# i3dPDK_A16K CFET_4T cell LEF (1x), from BE/CFET/4T/i3dPDK_A16K_0V7_27C_4T.lef:
# SITE i3d_16A added, coordinates on the 0.5nm grid (signal pins snapped outward, OBS outward).
# i3dPDK_A16K v1.0 (CC BY-NC-SA 4.0, Prof. Taigon Song, I3D VLSI Lab, KNU)
# Read after i3dPDK_A16K_4T_tech.lef.
VERSION 5.8 ;
BUSBITCHARS "[]" ;
DIVIDERCHAR "/" ;


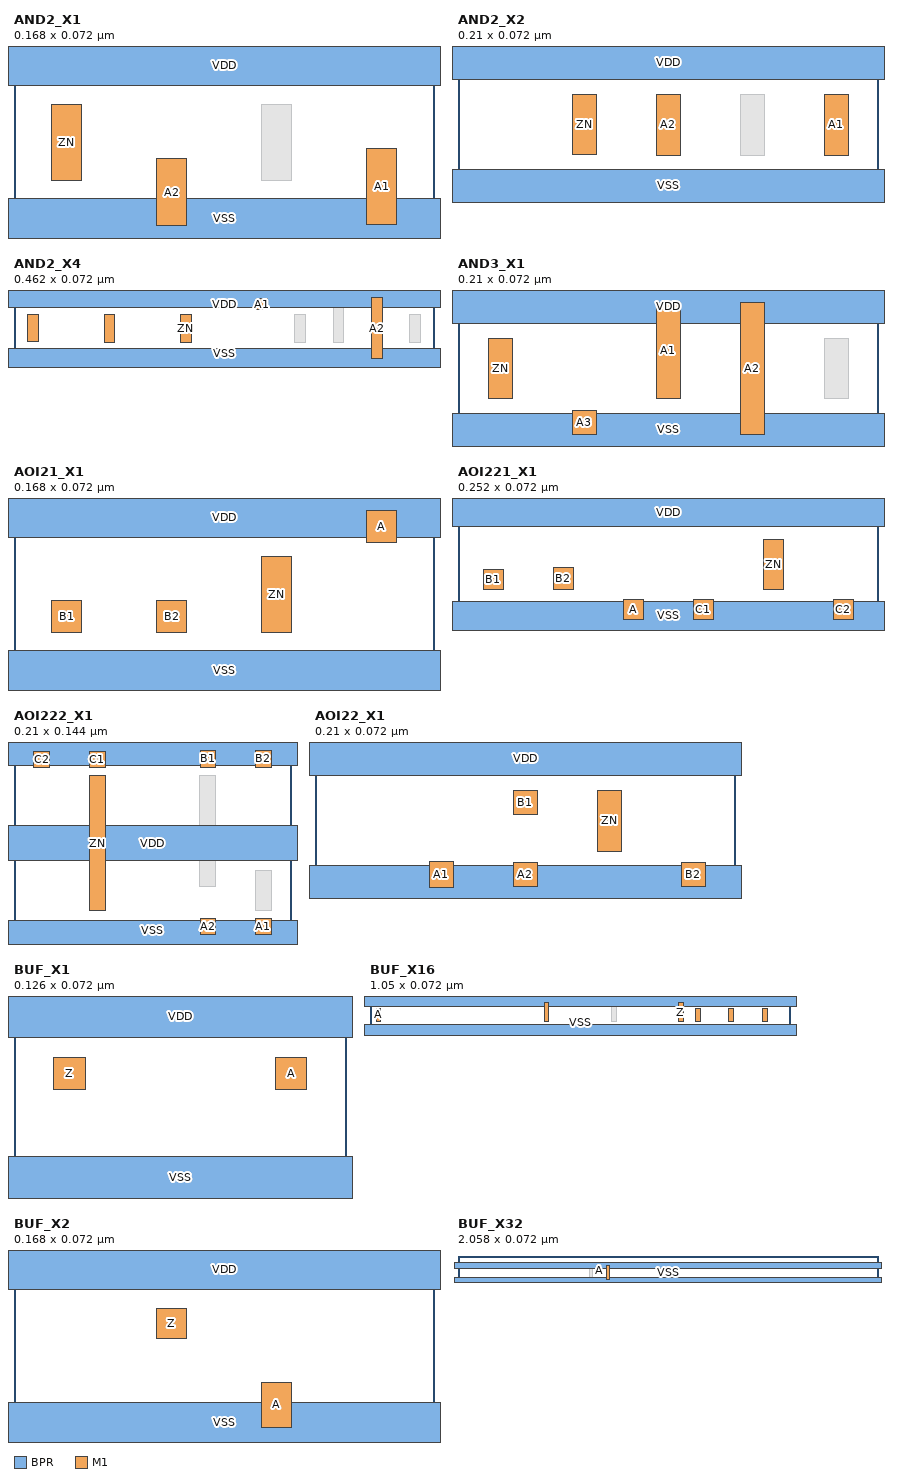
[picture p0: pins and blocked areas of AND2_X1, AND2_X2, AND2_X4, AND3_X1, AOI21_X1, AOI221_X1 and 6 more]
MACRO AND2_X1
  CLASS CORE ;
  FOREIGN AND2_X1 0 0 ;
  ORIGIN 0.0000 0.0000 ;
  SIZE 0.1680 BY 0.0720 ;
  SYMMETRY X Y ;
  SITE i3d_16A ;
  PIN VSS
    DIRECTION INOUT ;
    USE GROUND ;
    PORT
      LAYER BPR ;
        RECT -0.0160 -0.0135 0.1840 0.0135 ;
    END
  END VSS
  PIN VDD
    DIRECTION INOUT ;
    USE POWER ;
    PORT
      LAYER BPR ;
        RECT -0.0160 0.0585 0.1840 0.0855 ;
    END
  END VDD
  PIN A2
    DIRECTION INPUT ;
    USE SIGNAL ;
    PORT
      LAYER M1 ;
        RECT 0.0570 0.0025 0.0690 0.0295 ;
    END
  END A2
  PIN ZN
    DIRECTION OUTPUT ;
    USE SIGNAL ;
    PORT
      LAYER M1 ;
        RECT 0.0150 0.0205 0.0270 0.0510 ;
    END
  END ZN
  PIN A1
    DIRECTION INPUT ;
    USE SIGNAL ;
    PORT
      LAYER M1 ;
        RECT 0.1410 0.0030 0.1530 0.0335 ;
    END
  END A1
  OBS
    LAYER M1 ;
      RECT 0.0990 0.0205 0.1110 0.0510 ;
  END
END AND2_X1

MACRO AND2_X2
  CLASS CORE ;
  FOREIGN AND2_X2 0 0 ;
  ORIGIN 0.0000 0.0000 ;
  SIZE 0.2100 BY 0.0720 ;
  SYMMETRY X Y ;
  SITE i3d_16A ;
  PIN VDD
    DIRECTION INOUT ;
    USE POWER ;
    PORT
      LAYER BPR ;
        RECT -0.0160 0.0585 0.2260 0.0855 ;
    END
  END VDD
  PIN VSS
    DIRECTION INOUT ;
    USE GROUND ;
    PORT
      LAYER BPR ;
        RECT -0.0160 -0.0135 0.2260 0.0135 ;
    END
  END VSS
  PIN A1
    DIRECTION INPUT ;
    USE SIGNAL ;
    PORT
      LAYER M1 ;
        RECT 0.1830 0.0205 0.1950 0.0510 ;
    END
  END A1
  PIN A2
    DIRECTION INPUT ;
    USE SIGNAL ;
    PORT
      LAYER M1 ;
        RECT 0.0990 0.0205 0.1110 0.0510 ;
    END
  END A2
  PIN ZN
    DIRECTION OUTPUT ;
    USE SIGNAL ;
    PORT
      LAYER M1 ;
        RECT 0.0570 0.0210 0.0690 0.0510 ;
    END
  END ZN
  OBS
    LAYER M1 ;
      RECT 0.1410 0.0205 0.1530 0.0510 ;
  END
END AND2_X2

MACRO AND2_X4
  CLASS CORE ;
  FOREIGN AND2_X4 0 0 ;
  ORIGIN 0.0000 0.0000 ;
  SIZE 0.4620 BY 0.0720 ;
  SYMMETRY X Y ;
  SITE i3d_16A ;
  PIN VDD
    DIRECTION INOUT ;
    USE POWER ;
    PORT
      LAYER BPR ;
        RECT -0.0160 0.0585 0.4780 0.0855 ;
    END
  END VDD
  PIN VSS
    DIRECTION INOUT ;
    USE GROUND ;
    PORT
      LAYER BPR ;
        RECT -0.0160 -0.0135 0.4780 0.0135 ;
    END
  END VSS
  PIN ZN
    DIRECTION OUTPUT ;
    USE SIGNAL ;
    PORT
      LAYER M1 ;
        RECT 0.1830 0.0205 0.1950 0.0510 ;
        RECT 0.0990 0.0205 0.1110 0.0510 ;
        RECT 0.0150 0.0210 0.0270 0.0510 ;
    END
  END ZN
  PIN A1
    DIRECTION INPUT ;
    USE SIGNAL ;
    PORT
      LAYER M1 ;
        RECT 0.2670 0.0570 0.2790 0.0690 ;
    END
  END A1
  PIN A2
    DIRECTION INPUT ;
    USE SIGNAL ;
    PORT
      LAYER M1 ;
        RECT 0.3930 0.0025 0.4050 0.0695 ;
    END
  END A2
  OBS
    LAYER M1 ;
      RECT 0.4350 0.0205 0.4470 0.0510 ;
      RECT 0.3090 0.0205 0.3210 0.0510 ;
      RECT 0.3510 0.0205 0.3630 0.0695 ;
  END
END AND2_X4

MACRO AND3_X1
  CLASS CORE ;
  FOREIGN AND3_X1 0 0 ;
  ORIGIN 0.0000 0.0000 ;
  SIZE 0.2100 BY 0.0720 ;
  SYMMETRY X Y ;
  SITE i3d_16A ;
  PIN VSS
    DIRECTION INOUT ;
    USE GROUND ;
    PORT
      LAYER BPR ;
        RECT -0.0160 -0.0135 0.2260 0.0135 ;
    END
  END VSS
  PIN VDD
    DIRECTION INOUT ;
    USE POWER ;
    PORT
      LAYER BPR ;
        RECT -0.0160 0.0585 0.2260 0.0855 ;
    END
  END VDD
  PIN A3
    DIRECTION INPUT ;
    USE SIGNAL ;
    PORT
      LAYER M1 ;
        RECT 0.0570 0.0030 0.0690 0.0150 ;
    END
  END A3
  PIN ZN
    DIRECTION OUTPUT ;
    USE SIGNAL ;
    PORT
      LAYER M1 ;
        RECT 0.0150 0.0210 0.0270 0.0510 ;
    END
  END ZN
  PIN A2
    DIRECTION INPUT ;
    USE SIGNAL ;
    PORT
      LAYER M1 ;
        RECT 0.1410 0.0030 0.1530 0.0690 ;
    END
  END A2
  PIN A1
    DIRECTION INPUT ;
    USE SIGNAL ;
    PORT
      LAYER M1 ;
        RECT 0.0990 0.0210 0.1110 0.0690 ;
    END
  END A1
  OBS
    LAYER M1 ;
      RECT 0.1830 0.0210 0.1950 0.0510 ;
  END
END AND3_X1

MACRO AOI21_X1
  CLASS CORE ;
  FOREIGN AOI21_X1 0 0 ;
  ORIGIN 0.0000 0.0000 ;
  SIZE 0.1680 BY 0.0720 ;
  SYMMETRY X Y ;
  SITE i3d_16A ;
  PIN VDD
    DIRECTION INOUT ;
    USE POWER ;
    PORT
      LAYER BPR ;
        RECT -0.0160 0.0585 0.1840 0.0855 ;
    END
  END VDD
  PIN VSS
    DIRECTION INOUT ;
    USE GROUND ;
    PORT
      LAYER BPR ;
        RECT -0.0160 -0.0135 0.1840 0.0135 ;
    END
  END VSS
  PIN B1
    DIRECTION INPUT ;
    USE SIGNAL ;
    PORT
      LAYER M1 ;
        RECT 0.0150 0.0205 0.0270 0.0335 ;
    END
  END B1
  PIN A
    DIRECTION INPUT ;
    USE SIGNAL ;
    PORT
      LAYER M1 ;
        RECT 0.1410 0.0565 0.1530 0.0695 ;
    END
  END A
  PIN ZN
    DIRECTION OUTPUT ;
    USE SIGNAL ;
    PORT
      LAYER M1 ;
        RECT 0.0990 0.0205 0.1110 0.0510 ;
    END
  END ZN
  PIN B2
    DIRECTION INPUT ;
    USE SIGNAL ;
    PORT
      LAYER M1 ;
        RECT 0.0570 0.0205 0.0690 0.0335 ;
    END
  END B2
END AOI21_X1

MACRO AOI221_X1
  CLASS CORE ;
  FOREIGN AOI221_X1 0 0 ;
  ORIGIN 0.0000 0.0000 ;
  SIZE 0.2520 BY 0.0720 ;
  SYMMETRY X Y ;
  SITE i3d_16A ;
  PIN VSS
    DIRECTION INOUT ;
    USE GROUND ;
    PORT
      LAYER BPR ;
        RECT -0.0160 -0.0135 0.2680 0.0135 ;
    END
  END VSS
  PIN VDD
    DIRECTION INOUT ;
    USE POWER ;
    PORT
      LAYER BPR ;
        RECT -0.0160 0.0585 0.2680 0.0855 ;
    END
  END VDD
  PIN B1
    DIRECTION INPUT ;
    USE SIGNAL ;
    PORT
      LAYER M1 ;
        RECT 0.0150 0.0205 0.0270 0.0330 ;
    END
  END B1
  PIN A
    DIRECTION INPUT ;
    USE SIGNAL ;
    PORT
      LAYER M1 ;
        RECT 0.0990 0.0030 0.1110 0.0150 ;
    END
  END A
  PIN ZN
    DIRECTION OUTPUT ;
    USE SIGNAL ;
    PORT
      LAYER M1 ;
        RECT 0.1830 0.0205 0.1950 0.0510 ;
    END
  END ZN
  PIN B2
    DIRECTION INPUT ;
    USE SIGNAL ;
    PORT
      LAYER M1 ;
        RECT 0.0570 0.0210 0.0690 0.0340 ;
    END
  END B2
  PIN C2
    DIRECTION INPUT ;
    USE SIGNAL ;
    PORT
      LAYER M1 ;
        RECT 0.2250 0.0030 0.2370 0.0150 ;
    END
  END C2
  PIN C1
    DIRECTION INPUT ;
    USE SIGNAL ;
    PORT
      LAYER M1 ;
        RECT 0.1410 0.0030 0.1530 0.0150 ;
    END
  END C1
END AOI221_X1

MACRO AOI222_X1
  CLASS CORE ;
  FOREIGN AOI222_X1 0 0 ;
  ORIGIN 0.0000 0.0000 ;
  SIZE 0.2100 BY 0.1440 ;
  SYMMETRY X Y ;
  SITE i3d_16A ;
  PIN VDD
    DIRECTION INOUT ;
    USE POWER ;
    PORT
      LAYER BPR ;
        RECT -0.0160 0.0585 0.2260 0.0855 ;
    END
  END VDD
  PIN VSS
    DIRECTION INOUT ;
    USE GROUND ;
    PORT
      LAYER BPR ;
        RECT -0.0160 -0.0135 0.2260 0.0135 ;
        RECT -0.0160 0.1305 0.2260 0.1575 ;
    END
  END VSS
  PIN A1
    DIRECTION INPUT ;
    USE SIGNAL ;
    PORT
      LAYER M1 ;
        RECT 0.1830 0.0030 0.1950 0.0150 ;
    END
  END A1
  PIN A2
    DIRECTION INPUT ;
    USE SIGNAL ;
    PORT
      LAYER M1 ;
        RECT 0.1410 0.0030 0.1530 0.0150 ;
    END
  END A2
  PIN C2
    DIRECTION INPUT ;
    USE SIGNAL ;
    PORT
      LAYER M1 ;
        RECT 0.0150 0.1290 0.0270 0.1410 ;
    END
  END C2
  PIN C1
    DIRECTION INPUT ;
    USE SIGNAL ;
    PORT
      LAYER M1 ;
        RECT 0.0570 0.1290 0.0690 0.1410 ;
    END
  END C1
  PIN B1
    DIRECTION INPUT ;
    USE SIGNAL ;
    PORT
      LAYER M1 ;
        RECT 0.1410 0.1295 0.1530 0.1420 ;
    END
  END B1
  PIN B2
    DIRECTION INPUT ;
    USE SIGNAL ;
    PORT
      LAYER M1 ;
        RECT 0.1830 0.1295 0.1950 0.1420 ;
    END
  END B2
  PIN ZN
    DIRECTION OUTPUT ;
    USE SIGNAL ;
    PORT
      LAYER M1 ;
        RECT 0.0570 0.0205 0.0690 0.1230 ;
    END
  END ZN
  OBS
    LAYER M1 ;
      RECT 0.1830 0.0205 0.1950 0.0510 ;
      RECT 0.1405 0.0390 0.1530 0.1230 ;
  END
END AOI222_X1

MACRO AOI22_X1
  CLASS CORE ;
  FOREIGN AOI22_X1 0 0 ;
  ORIGIN 0.0000 0.0000 ;
  SIZE 0.2100 BY 0.0720 ;
  SYMMETRY X Y ;
  SITE i3d_16A ;
  PIN VSS
    DIRECTION INOUT ;
    USE GROUND ;
    PORT
      LAYER BPR ;
        RECT -0.0160 -0.0135 0.2260 0.0135 ;
    END
  END VSS
  PIN VDD
    DIRECTION INOUT ;
    USE POWER ;
    PORT
      LAYER BPR ;
        RECT -0.0160 0.0585 0.2260 0.0855 ;
    END
  END VDD
  PIN ZN
    DIRECTION OUTPUT ;
    USE SIGNAL ;
    PORT
      LAYER M1 ;
        RECT 0.1410 0.0205 0.1530 0.0510 ;
    END
  END ZN
  PIN B2
    DIRECTION INPUT ;
    USE SIGNAL ;
    PORT
      LAYER M1 ;
        RECT 0.1830 0.0030 0.1950 0.0150 ;
    END
  END B2
  PIN A1
    DIRECTION INPUT ;
    USE SIGNAL ;
    PORT
      LAYER M1 ;
        RECT 0.0570 0.0025 0.0690 0.0155 ;
    END
  END A1
  PIN A2
    DIRECTION INPUT ;
    USE SIGNAL ;
    PORT
      LAYER M1 ;
        RECT 0.0990 0.0030 0.1110 0.0150 ;
    END
  END A2
  PIN B1
    DIRECTION INPUT ;
    USE SIGNAL ;
    PORT
      LAYER M1 ;
        RECT 0.0990 0.0390 0.1110 0.0510 ;
    END
  END B1
END AOI22_X1

MACRO BUF_X1
  CLASS CORE ;
  FOREIGN BUF_X1 0 0 ;
  ORIGIN 0.0000 0.0000 ;
  SIZE 0.1260 BY 0.0720 ;
  SYMMETRY X Y ;
  SITE i3d_16A ;
  PIN VSS
    DIRECTION INOUT ;
    USE GROUND ;
    PORT
      LAYER BPR ;
        RECT -0.0160 -0.0135 0.1420 0.0135 ;
    END
  END VSS
  PIN VDD
    DIRECTION INOUT ;
    USE POWER ;
    PORT
      LAYER BPR ;
        RECT -0.0160 0.0585 0.1420 0.0855 ;
    END
  END VDD
  PIN A
    DIRECTION INPUT ;
    USE SIGNAL ;
    PORT
      LAYER M1 ;
        RECT 0.0990 0.0390 0.1110 0.0510 ;
    END
  END A
  PIN Z
    DIRECTION OUTPUT ;
    USE SIGNAL ;
    PORT
      LAYER M1 ;
        RECT 0.0150 0.0390 0.0270 0.0510 ;
    END
  END Z
END BUF_X1

MACRO BUF_X16
  CLASS CORE ;
  FOREIGN BUF_X16 0 0 ;
  ORIGIN 0.0000 0.0000 ;
  SIZE 1.0500 BY 0.0720 ;
  SYMMETRY X Y ;
  SITE i3d_16A ;
  PIN VSS
    DIRECTION INOUT ;
    USE GROUND ;
    PORT
      LAYER BPR ;
        RECT -0.0160 -0.0135 1.0660 0.0135 ;
    END
  END VSS
  PIN VDD
    DIRECTION INOUT ;
    USE POWER ;
    PORT
      LAYER BPR ;
        RECT -0.0160 0.0585 1.0660 0.0855 ;
    END
  END VDD
  PIN A
    DIRECTION INPUT ;
    USE SIGNAL ;
    PORT
      LAYER M1 ;
        RECT 0.0150 0.0215 0.0270 0.0540 ;
    END
  END A
  PIN Z
    DIRECTION OUTPUT ;
    USE SIGNAL ;
    PORT
      LAYER M1 ;
        RECT 0.9810 0.0205 0.9930 0.0550 ;
        RECT 0.8970 0.0205 0.9090 0.0550 ;
        RECT 0.7710 0.0205 0.7830 0.0685 ;
        RECT 0.8130 0.0205 0.8250 0.0550 ;
        RECT 0.4350 0.0205 0.4470 0.0685 ;
    END
  END Z
  OBS
    LAYER M1 ;
      RECT 0.6030 0.0205 0.6150 0.0685 ;
  END
END BUF_X16

MACRO BUF_X2
  CLASS CORE ;
  FOREIGN BUF_X2 0 0 ;
  ORIGIN 0.0000 0.0000 ;
  SIZE 0.1680 BY 0.0720 ;
  SYMMETRY X Y ;
  SITE i3d_16A ;
  PIN VSS
    DIRECTION INOUT ;
    USE GROUND ;
    PORT
      LAYER BPR ;
        RECT -0.0160 -0.0135 0.1840 0.0135 ;
    END
  END VSS
  PIN VDD
    DIRECTION INOUT ;
    USE POWER ;
    PORT
      LAYER BPR ;
        RECT -0.0160 0.0585 0.1840 0.0855 ;
    END
  END VDD
  PIN Z
    DIRECTION OUTPUT ;
    USE SIGNAL ;
    PORT
      LAYER M1 ;
        RECT 0.0570 0.0390 0.0690 0.0510 ;
    END
  END Z
  PIN A
    DIRECTION INPUT ;
    USE SIGNAL ;
    PORT
      LAYER M1 ;
        RECT 0.0990 0.0035 0.1110 0.0215 ;
    END
  END A
END BUF_X2

MACRO BUF_X32
  CLASS CORE ;
  FOREIGN BUF_X32 0 0 ;
  ORIGIN 0.0000 0.0000 ;
  SIZE 2.0580 BY 0.0720 ;
  SYMMETRY X Y ;
  SITE i3d_16A ;
  PIN VSS
    DIRECTION INOUT ;
    USE GROUND ;
    PORT
      LAYER BPR ;
        RECT -0.0160 -0.0135 2.0740 0.0135 ;
    END
  END VSS
  PIN VDD
    DIRECTION INOUT ;
    USE POWER ;
    PORT
      LAYER BPR ;
        RECT -0.0160 0.0585 2.0740 0.0855 ;
    END
  END VDD
  PIN A
    DIRECTION INPUT ;
    USE SIGNAL ;
    PORT
      LAYER M1 ;
        RECT 0.6870 0.0385 0.6990 0.0525 ;
    END
  END A
  PIN Z
    DIRECTION OUTPUT ;
    USE SIGNAL ;
    PORT
      LAYER M1 ;
        RECT 0.7290 0.0030 0.7410 0.0690 ;
    END
  END Z
  OBS
    LAYER M1 ;
      RECT 0.6450 0.0030 0.6570 0.0690 ;
  END
END BUF_X32

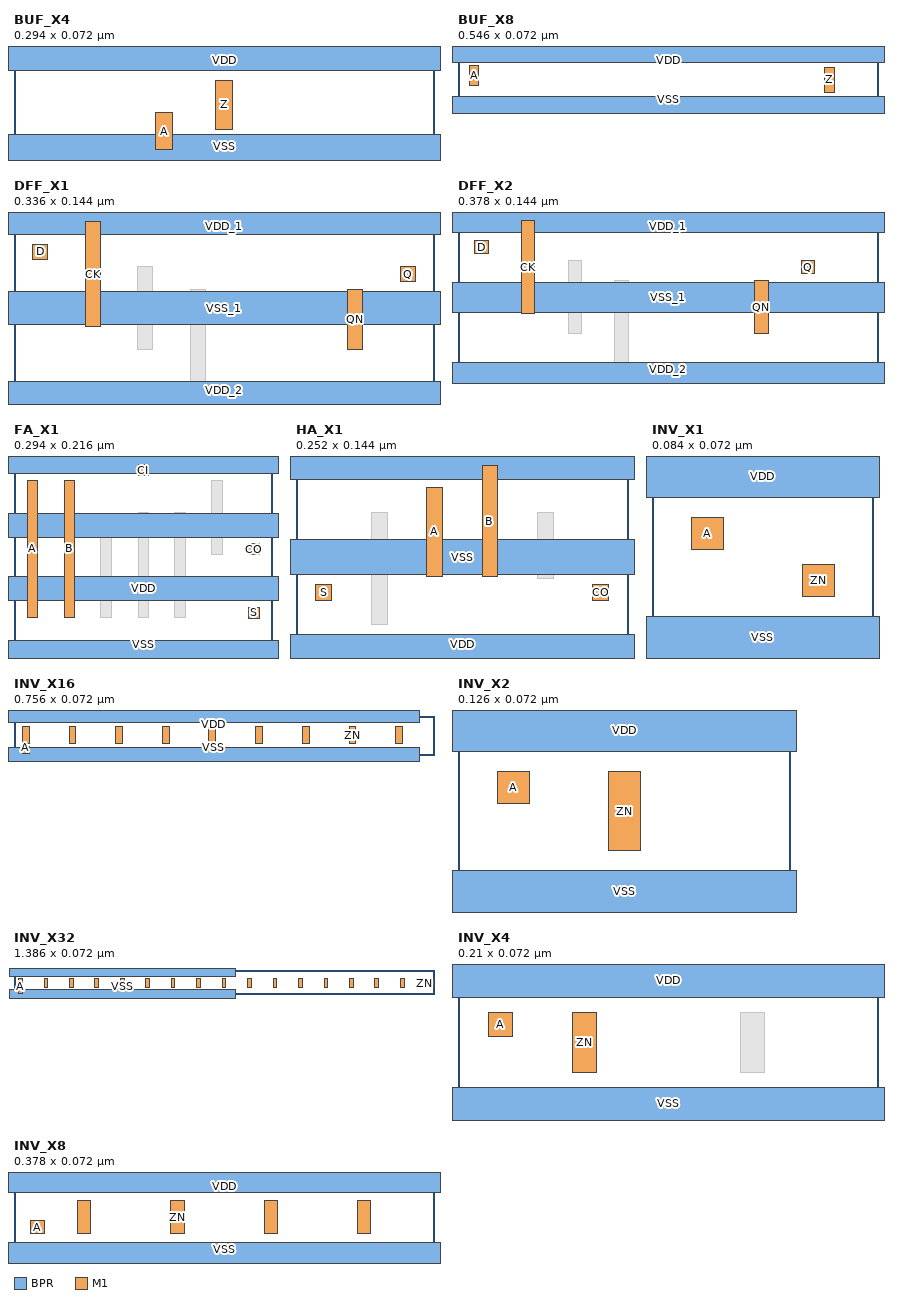
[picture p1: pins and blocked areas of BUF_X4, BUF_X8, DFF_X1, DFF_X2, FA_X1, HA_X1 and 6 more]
MACRO BUF_X4
  CLASS CORE ;
  FOREIGN BUF_X4 0 0 ;
  ORIGIN 0.0000 0.0000 ;
  SIZE 0.2940 BY 0.0720 ;
  SYMMETRY X Y ;
  SITE i3d_16A ;
  PIN VDD
    DIRECTION INOUT ;
    USE POWER ;
    PORT
      LAYER BPR ;
        RECT -0.0160 0.0585 0.3100 0.0855 ;
    END
  END VDD
  PIN VSS
    DIRECTION INOUT ;
    USE GROUND ;
    PORT
      LAYER BPR ;
        RECT -0.0160 -0.0135 0.3100 0.0135 ;
    END
  END VSS
  PIN Z
    DIRECTION OUTPUT ;
    USE SIGNAL ;
    PORT
      LAYER M1 ;
        RECT 0.1410 0.0175 0.1530 0.0515 ;
    END
  END Z
  PIN A
    DIRECTION INPUT ;
    USE SIGNAL ;
    PORT
      LAYER M1 ;
        RECT 0.0990 0.0030 0.1110 0.0290 ;
    END
  END A
END BUF_X4

MACRO BUF_X8
  CLASS CORE ;
  FOREIGN BUF_X8 0 0 ;
  ORIGIN 0.0000 0.0000 ;
  SIZE 0.5460 BY 0.0720 ;
  SYMMETRY X Y ;
  SITE i3d_16A ;
  PIN VDD
    DIRECTION INOUT ;
    USE POWER ;
    PORT
      LAYER BPR ;
        RECT -0.0160 0.0585 0.5620 0.0855 ;
    END
  END VDD
  PIN VSS
    DIRECTION INOUT ;
    USE GROUND ;
    PORT
      LAYER BPR ;
        RECT -0.0160 -0.0135 0.5620 0.0135 ;
    END
  END VSS
  PIN A
    DIRECTION INPUT ;
    USE SIGNAL ;
    PORT
      LAYER M1 ;
        RECT 0.0150 0.0275 0.0270 0.0540 ;
    END
  END A
  PIN Z
    DIRECTION OUTPUT ;
    USE SIGNAL ;
    PORT
      LAYER M1 ;
        RECT 0.4770 0.0190 0.4890 0.0515 ;
    END
  END Z
END BUF_X8

MACRO DFF_X1
  CLASS CORE ;
  FOREIGN DFF_X1 0 0 ;
  ORIGIN 0.0000 0.0000 ;
  SIZE 0.3360 BY 0.1440 ;
  SYMMETRY X Y ;
  SITE i3d_16A ;
  PIN VDD_1
    DIRECTION INOUT ;
    USE POWER ;
    PORT
      LAYER BPR ;
        RECT -0.0160 0.1305 0.3520 0.1575 ;
    END
  END VDD_1
  PIN VDD_2
    DIRECTION INOUT ;
    USE POWER ;
    PORT
      LAYER BPR ;
        RECT -0.0160 -0.0135 0.3520 0.0135 ;
    END
  END VDD_2
  PIN VSS_1
    DIRECTION INOUT ;
    USE GROUND ;
    PORT
      LAYER BPR ;
        RECT -0.0160 0.0585 0.3520 0.0855 ;
    END
  END VSS_1
  PIN CK
    DIRECTION INPUT ;
    USE CLOCK ;
    PORT
      LAYER M1 ;
        RECT 0.0570 0.0570 0.0690 0.1410 ;
    END
  END CK
  PIN Q
    DIRECTION OUTPUT ;
    USE SIGNAL ;
    PORT
      LAYER M1 ;
        RECT 0.3090 0.0930 0.3210 0.1050 ;
    END
  END Q
  PIN QN
    DIRECTION OUTPUT ;
    USE SIGNAL ;
    PORT
      LAYER M1 ;
        RECT 0.2670 0.0390 0.2790 0.0870 ;
    END
  END QN
  PIN D
    DIRECTION INPUT ;
    USE SIGNAL ;
    PORT
      LAYER M1 ;
        RECT 0.0150 0.1110 0.0270 0.1230 ;
    END
  END D
  OBS
    LAYER M1 ;
      RECT 0.0990 0.0390 0.1110 0.1050 ;
      RECT 0.1410 0.0030 0.1530 0.0870 ;
  END
END DFF_X1

MACRO DFF_X2
  CLASS CORE ;
  FOREIGN DFF_X2 0 0 ;
  ORIGIN 0.0000 0.0000 ;
  SIZE 0.3780 BY 0.1440 ;
  SYMMETRY X Y ;
  SITE i3d_16A ;
  PIN VSS_1
    DIRECTION INOUT ;
    USE GROUND ;
    PORT
      LAYER BPR ;
        RECT -0.0160 0.0585 0.3940 0.0855 ;
    END
  END VSS_1
  PIN VDD_2
    DIRECTION INOUT ;
    USE POWER ;
    PORT
      LAYER BPR ;
        RECT -0.0160 -0.0135 0.3940 0.0135 ;
    END
  END VDD_2
  PIN VDD_1
    DIRECTION INOUT ;
    USE POWER ;
    PORT
      LAYER BPR ;
        RECT -0.0160 0.1305 0.3940 0.1575 ;
    END
  END VDD_1
  PIN QN
    DIRECTION OUTPUT ;
    USE SIGNAL ;
    PORT
      LAYER M1 ;
        RECT 0.2670 0.0390 0.2790 0.0870 ;
    END
  END QN
  PIN Q
    DIRECTION OUTPUT ;
    USE SIGNAL ;
    PORT
      LAYER M1 ;
        RECT 0.3090 0.0930 0.3210 0.1050 ;
    END
  END Q
  PIN CK
    DIRECTION INPUT ;
    USE CLOCK ;
    PORT
      LAYER M1 ;
        RECT 0.0570 0.0570 0.0690 0.1410 ;
    END
  END CK
  PIN D
    DIRECTION INPUT ;
    USE SIGNAL ;
    PORT
      LAYER M1 ;
        RECT 0.0150 0.1110 0.0270 0.1230 ;
    END
  END D
  OBS
    LAYER M1 ;
      RECT 0.1410 0.0030 0.1530 0.0870 ;
      RECT 0.0990 0.0390 0.1110 0.1050 ;
  END
END DFF_X2

MACRO FA_X1
  CLASS CORE ;
  FOREIGN FA_X1 0 0 ;
  ORIGIN 0.0000 0.0000 ;
  SIZE 0.2940 BY 0.2160 ;
  SYMMETRY X Y ;
  SITE i3d_16A ;
  PIN VDD
    DIRECTION INOUT ;
    USE POWER ;
    PORT
      LAYER BPR ;
        RECT -0.0160 0.2025 0.3100 0.2295 ;
        RECT -0.0160 0.0585 0.3100 0.0855 ;
    END
  END VDD
  PIN VSS
    DIRECTION INOUT ;
    USE GROUND ;
    PORT
      LAYER BPR ;
        RECT -0.0160 -0.0135 0.3100 0.0135 ;
        RECT -0.0160 0.1305 0.3100 0.1575 ;
    END
  END VSS
  PIN CI
    DIRECTION INPUT ;
    USE SIGNAL ;
    PORT
      LAYER M1 ;
        RECT 0.1410 0.2010 0.1530 0.2135 ;
    END
  END CI
  PIN S
    DIRECTION OUTPUT ;
    USE SIGNAL ;
    PORT
      LAYER M1 ;
        RECT 0.2670 0.0385 0.2790 0.0510 ;
    END
  END S
  PIN CO
    DIRECTION OUTPUT ;
    USE SIGNAL ;
    PORT
      LAYER M1 ;
        RECT 0.2670 0.1110 0.2790 0.1230 ;
    END
  END CO
  PIN B
    DIRECTION INPUT ;
    USE SIGNAL ;
    PORT
      LAYER M1 ;
        RECT 0.0570 0.0390 0.0690 0.1955 ;
    END
  END B
  PIN A
    DIRECTION INPUT ;
    USE SIGNAL ;
    PORT
      LAYER M1 ;
        RECT 0.0150 0.0390 0.0270 0.1955 ;
    END
  END A
  OBS
    LAYER M1 ;
      RECT 0.1830 0.1465 0.1950 0.1590 ;
      RECT 0.1410 0.0390 0.1530 0.1590 ;
      RECT 0.0985 0.0390 0.1110 0.1410 ;
      RECT 0.2245 0.1110 0.2370 0.1950 ;
      RECT 0.1830 0.0390 0.1950 0.1410 ;
  END
END FA_X1

MACRO HA_X1
  CLASS CORE ;
  FOREIGN HA_X1 0 0 ;
  ORIGIN 0.0000 0.0000 ;
  SIZE 0.2520 BY 0.1440 ;
  SYMMETRY X Y ;
  SITE i3d_16A ;
  PIN VDD
    DIRECTION INOUT ;
    USE POWER ;
    PORT
      LAYER BPR ;
        RECT -0.0160 -0.0135 0.2680 0.0135 ;
        RECT -0.0160 0.1305 0.2680 0.1575 ;
    END
  END VDD
  PIN VSS
    DIRECTION INOUT ;
    USE GROUND ;
    PORT
      LAYER BPR ;
        RECT -0.0160 0.0585 0.2680 0.0855 ;
    END
  END VSS
  PIN A
    DIRECTION INPUT ;
    USE SIGNAL ;
    PORT
      LAYER M1 ;
        RECT 0.0990 0.0575 0.1110 0.1245 ;
    END
  END A
  PIN S
    DIRECTION OUTPUT ;
    USE SIGNAL ;
    PORT
      LAYER M1 ;
        RECT 0.0150 0.0390 0.0270 0.0510 ;
    END
  END S
  PIN B
    DIRECTION INPUT ;
    USE SIGNAL ;
    PORT
      LAYER M1 ;
        RECT 0.1410 0.0570 0.1530 0.1415 ;
    END
  END B
  PIN CO
    DIRECTION OUTPUT ;
    USE SIGNAL ;
    PORT
      LAYER M1 ;
        RECT 0.2250 0.0390 0.2370 0.0510 ;
    END
  END CO
  OBS
    LAYER M1 ;
      RECT 0.1830 0.0560 0.1950 0.1055 ;
      RECT 0.0570 0.0205 0.0690 0.1055 ;
  END
END HA_X1

MACRO INV_X1
  CLASS CORE ;
  FOREIGN INV_X1 0 0 ;
  ORIGIN 0.0000 0.0000 ;
  SIZE 0.0840 BY 0.0720 ;
  SYMMETRY X Y ;
  SITE i3d_16A ;
  PIN VDD
    DIRECTION INOUT ;
    USE POWER ;
    PORT
      LAYER BPR ;
        RECT -0.0160 0.0585 0.1000 0.0855 ;
    END
  END VDD
  PIN VSS
    DIRECTION INOUT ;
    USE GROUND ;
    PORT
      LAYER BPR ;
        RECT -0.0160 -0.0135 0.1000 0.0135 ;
    END
  END VSS
  PIN A
    DIRECTION INPUT ;
    USE SIGNAL ;
    PORT
      LAYER M1 ;
        RECT 0.0150 0.0390 0.0270 0.0510 ;
    END
  END A
  PIN ZN
    DIRECTION OUTPUT ;
    USE SIGNAL ;
    PORT
      LAYER M1 ;
        RECT 0.0570 0.0210 0.0690 0.0330 ;
    END
  END ZN
END INV_X1

MACRO INV_X16
  CLASS CORE ;
  FOREIGN INV_X16 0 0 ;
  ORIGIN 0.0000 0.0000 ;
  SIZE 0.7560 BY 0.0720 ;
  SYMMETRY X Y ;
  SITE i3d_16A ;
  PIN VSS
    DIRECTION INOUT ;
    USE GROUND ;
    PORT
      LAYER BPR ;
        RECT -0.0160 -0.0135 0.7300 0.0135 ;
    END
  END VSS
  PIN VDD
    DIRECTION INOUT ;
    USE POWER ;
    PORT
      LAYER BPR ;
        RECT -0.0160 0.0585 0.7300 0.0855 ;
    END
  END VDD
  PIN A
    DIRECTION INPUT ;
    USE SIGNAL ;
    PORT
      LAYER M1 ;
        RECT 0.0150 0.0030 0.0270 0.0155 ;
    END
  END A
  PIN ZN
    DIRECTION OUTPUT ;
    USE SIGNAL ;
    PORT
      LAYER M1 ;
        RECT 0.6870 0.0210 0.6990 0.0510 ;
        RECT 0.6030 0.0210 0.6150 0.0510 ;
        RECT 0.5190 0.0210 0.5310 0.0510 ;
        RECT 0.4350 0.0210 0.4470 0.0510 ;
        RECT 0.3510 0.0210 0.3630 0.0510 ;
        RECT 0.2670 0.0210 0.2790 0.0510 ;
        RECT 0.1830 0.0210 0.1950 0.0510 ;
        RECT 0.0990 0.0210 0.1110 0.0510 ;
        RECT 0.0150 0.0210 0.0270 0.0510 ;
    END
  END ZN
END INV_X16

MACRO INV_X2
  CLASS CORE ;
  FOREIGN INV_X2 0 0 ;
  ORIGIN 0.0000 0.0000 ;
  SIZE 0.1260 BY 0.0720 ;
  SYMMETRY X Y ;
  SITE i3d_16A ;
  PIN VDD
    DIRECTION INOUT ;
    USE POWER ;
    PORT
      LAYER BPR ;
        RECT -0.0160 0.0585 0.1420 0.0855 ;
    END
  END VDD
  PIN VSS
    DIRECTION INOUT ;
    USE GROUND ;
    PORT
      LAYER BPR ;
        RECT -0.0160 -0.0135 0.1420 0.0135 ;
    END
  END VSS
  PIN A
    DIRECTION INPUT ;
    USE SIGNAL ;
    PORT
      LAYER M1 ;
        RECT 0.0150 0.0390 0.0270 0.0510 ;
    END
  END A
  PIN ZN
    DIRECTION OUTPUT ;
    USE SIGNAL ;
    PORT
      LAYER M1 ;
        RECT 0.0570 0.0210 0.0690 0.0510 ;
    END
  END ZN
END INV_X2

MACRO INV_X32
  CLASS CORE ;
  FOREIGN INV_X32 0 0 ;
  ORIGIN 0.0000 0.0000 ;
  SIZE 1.3860 BY 0.0720 ;
  SYMMETRY X Y ;
  SITE i3d_16A ;
  PIN VSS
    DIRECTION INOUT ;
    USE GROUND ;
    PORT
      LAYER BPR ;
        RECT -0.0160 -0.0135 0.7300 0.0135 ;
    END
  END VSS
  PIN VDD
    DIRECTION INOUT ;
    USE POWER ;
    PORT
      LAYER BPR ;
        RECT -0.0160 0.0585 0.7300 0.0855 ;
    END
  END VDD
  PIN A
    DIRECTION INPUT ;
    USE SIGNAL ;
    PORT
      LAYER M1 ;
        RECT 0.0150 0.0030 0.0270 0.0155 ;
    END
  END A
  PIN ZN
    DIRECTION OUTPUT ;
    USE SIGNAL ;
    PORT
      LAYER M1 ;
        RECT 1.3590 0.0210 1.3710 0.0510 ;
        RECT 1.2750 0.0210 1.2870 0.0510 ;
        RECT 1.1910 0.0210 1.2030 0.0510 ;
        RECT 1.1070 0.0210 1.1190 0.0510 ;
        RECT 1.0230 0.0210 1.0350 0.0510 ;
        RECT 0.9390 0.0210 0.9510 0.0510 ;
        RECT 0.8550 0.0210 0.8670 0.0510 ;
        RECT 0.7710 0.0210 0.7830 0.0510 ;
        RECT 0.6870 0.0210 0.6990 0.0510 ;
        RECT 0.6030 0.0210 0.6150 0.0510 ;
        RECT 0.5190 0.0210 0.5310 0.0510 ;
        RECT 0.4350 0.0210 0.4470 0.0510 ;
        RECT 0.3510 0.0210 0.3630 0.0510 ;
        RECT 0.2670 0.0210 0.2790 0.0510 ;
        RECT 0.1830 0.0210 0.1950 0.0510 ;
        RECT 0.0990 0.0210 0.1110 0.0510 ;
        RECT 0.0150 0.0210 0.0270 0.0510 ;
    END
  END ZN
END INV_X32

MACRO INV_X4
  CLASS CORE ;
  FOREIGN INV_X4 0 0 ;
  ORIGIN 0.0000 0.0000 ;
  SIZE 0.2100 BY 0.0720 ;
  SYMMETRY X Y ;
  SITE i3d_16A ;
  PIN VDD
    DIRECTION INOUT ;
    USE POWER ;
    PORT
      LAYER BPR ;
        RECT -0.0160 0.0585 0.2260 0.0855 ;
    END
  END VDD
  PIN VSS
    DIRECTION INOUT ;
    USE GROUND ;
    PORT
      LAYER BPR ;
        RECT -0.0160 -0.0135 0.2260 0.0135 ;
    END
  END VSS
  PIN A
    DIRECTION INPUT ;
    USE SIGNAL ;
    PORT
      LAYER M1 ;
        RECT 0.0150 0.0390 0.0270 0.0510 ;
    END
  END A
  PIN ZN
    DIRECTION OUTPUT ;
    USE SIGNAL ;
    PORT
      LAYER M1 ;
        RECT 0.0570 0.0210 0.0690 0.0510 ;
    END
  END ZN
  OBS
    LAYER M1 ;
      RECT 0.1410 0.0210 0.1530 0.0510 ;
  END
END INV_X4

MACRO INV_X8
  CLASS CORE ;
  FOREIGN INV_X8 0 0 ;
  ORIGIN 0.0000 0.0000 ;
  SIZE 0.3780 BY 0.0720 ;
  SYMMETRY X Y ;
  SITE i3d_16A ;
  PIN VDD
    DIRECTION INOUT ;
    USE POWER ;
    PORT
      LAYER BPR ;
        RECT -0.0160 0.0585 0.3940 0.0855 ;
    END
  END VDD
  PIN VSS
    DIRECTION INOUT ;
    USE GROUND ;
    PORT
      LAYER BPR ;
        RECT -0.0160 -0.0135 0.3940 0.0135 ;
    END
  END VSS
  PIN A
    DIRECTION INPUT ;
    USE SIGNAL ;
    PORT
      LAYER M1 ;
        RECT 0.0150 0.0210 0.0270 0.0330 ;
    END
  END A
  PIN ZN
    DIRECTION OUTPUT ;
    USE SIGNAL ;
    PORT
      LAYER M1 ;
        RECT 0.0570 0.0210 0.0690 0.0510 ;
        RECT 0.1410 0.0210 0.1530 0.0510 ;
        RECT 0.2250 0.0210 0.2370 0.0510 ;
        RECT 0.3090 0.0210 0.3210 0.0510 ;
    END
  END ZN
END INV_X8

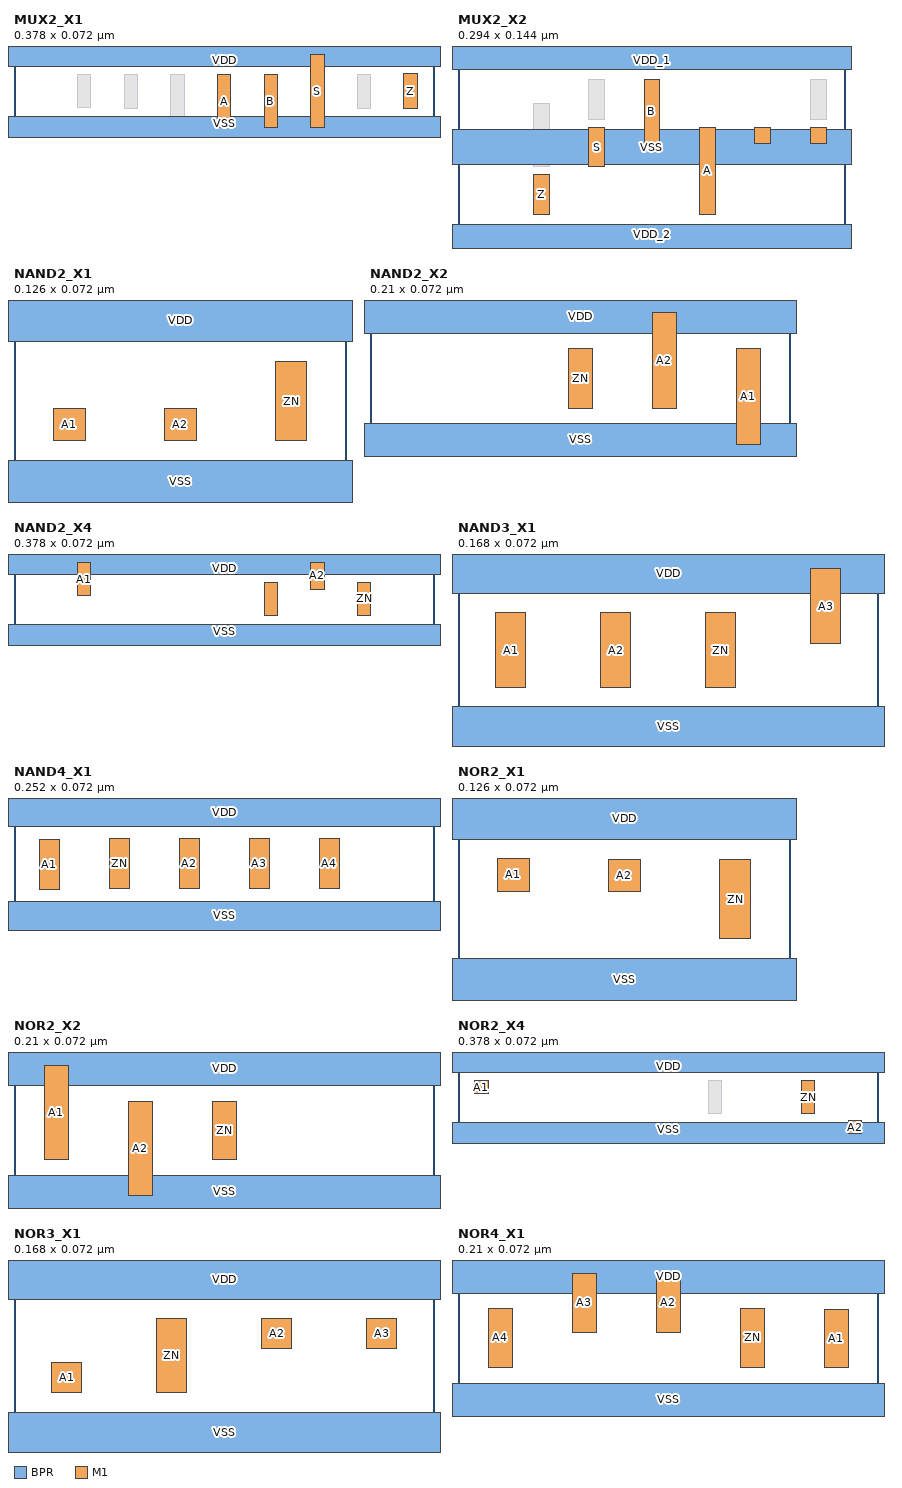
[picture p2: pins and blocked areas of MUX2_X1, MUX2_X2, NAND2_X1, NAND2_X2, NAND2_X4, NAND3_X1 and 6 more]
MACRO MUX2_X1
  CLASS CORE ;
  FOREIGN MUX2_X1 0 0 ;
  ORIGIN 0.0000 0.0000 ;
  SIZE 0.3780 BY 0.0720 ;
  SYMMETRY X Y ;
  SITE i3d_16A ;
  PIN VDD
    DIRECTION INOUT ;
    USE POWER ;
    PORT
      LAYER BPR ;
        RECT -0.0160 0.0585 0.3940 0.0855 ;
    END
  END VDD
  PIN VSS
    DIRECTION INOUT ;
    USE GROUND ;
    PORT
      LAYER BPR ;
        RECT -0.0160 -0.0135 0.3940 0.0135 ;
    END
  END VSS
  PIN A
    DIRECTION INPUT ;
    USE SIGNAL ;
    PORT
      LAYER M1 ;
        RECT 0.1830 0.0030 0.1950 0.0510 ;
    END
  END A
  PIN B
    DIRECTION INPUT ;
    USE SIGNAL ;
    PORT
      LAYER M1 ;
        RECT 0.2250 0.0030 0.2370 0.0510 ;
    END
  END B
  PIN S
    DIRECTION INPUT ;
    USE SIGNAL ;
    PORT
      LAYER M1 ;
        RECT 0.2670 0.0030 0.2790 0.0690 ;
    END
  END S
  PIN Z
    DIRECTION OUTPUT ;
    USE SIGNAL ;
    PORT
      LAYER M1 ;
        RECT 0.3510 0.0205 0.3630 0.0515 ;
    END
  END Z
  OBS
    LAYER M1 ;
      RECT 0.1410 0.0030 0.1530 0.0510 ;
      RECT 0.3090 0.0205 0.3210 0.0510 ;
      RECT 0.0990 0.0205 0.1110 0.0510 ;
      RECT 0.0570 0.0210 0.0690 0.0510 ;
  END
END MUX2_X1

MACRO MUX2_X2
  CLASS CORE ;
  FOREIGN MUX2_X2 0 0 ;
  ORIGIN 0.0000 0.0000 ;
  SIZE 0.2940 BY 0.1440 ;
  SYMMETRY X Y ;
  SITE i3d_16A ;
  PIN VDD_2
    DIRECTION INOUT ;
    USE POWER ;
    PORT
      LAYER BPR ;
        RECT -0.0160 -0.0135 0.3100 0.0135 ;
    END
  END VDD_2
  PIN VSS
    DIRECTION INOUT ;
    USE GROUND ;
    PORT
      LAYER BPR ;
        RECT -0.0160 0.0585 0.3100 0.0855 ;
    END
  END VSS
  PIN VDD_1
    DIRECTION INOUT ;
    USE POWER ;
    PORT
      LAYER BPR ;
        RECT -0.0160 0.1305 0.3100 0.1575 ;
    END
  END VDD_1
  PIN A
    DIRECTION INPUT ;
    USE SIGNAL ;
    PORT
      LAYER M1 ;
        RECT 0.2250 0.0750 0.2370 0.0870 ;
        RECT 0.1830 0.0210 0.1950 0.0870 ;
    END
  END A
  PIN B
    DIRECTION INPUT ;
    USE SIGNAL ;
    PORT
      LAYER M1 ;
        RECT 0.1410 0.0750 0.1530 0.1230 ;
        RECT 0.2670 0.0750 0.2790 0.0870 ;
    END
  END B
  PIN Z
    DIRECTION OUTPUT ;
    USE SIGNAL ;
    PORT
      LAYER M1 ;
        RECT 0.0570 0.0210 0.0690 0.0510 ;
    END
  END Z
  PIN S
    DIRECTION INPUT ;
    USE SIGNAL ;
    PORT
      LAYER M1 ;
        RECT 0.0990 0.0570 0.1110 0.0870 ;
    END
  END S
  OBS
    LAYER M1 ;
      RECT 0.0990 0.0930 0.1110 0.1230 ;
      RECT 0.2670 0.0930 0.2790 0.1230 ;
      RECT 0.0570 0.0570 0.0690 0.1050 ;
  END
END MUX2_X2

MACRO NAND2_X1
  CLASS CORE ;
  FOREIGN NAND2_X1 0 0 ;
  ORIGIN 0.0000 0.0000 ;
  SIZE 0.1260 BY 0.0720 ;
  SYMMETRY X Y ;
  SITE i3d_16A ;
  PIN VSS
    DIRECTION INOUT ;
    USE GROUND ;
    PORT
      LAYER BPR ;
        RECT -0.0160 -0.0135 0.1420 0.0135 ;
    END
  END VSS
  PIN VDD
    DIRECTION INOUT ;
    USE POWER ;
    PORT
      LAYER BPR ;
        RECT -0.0160 0.0585 0.1420 0.0855 ;
    END
  END VDD
  PIN ZN
    DIRECTION OUTPUT ;
    USE SIGNAL ;
    PORT
      LAYER M1 ;
        RECT 0.0990 0.0210 0.1110 0.0510 ;
    END
  END ZN
  PIN A2
    DIRECTION INPUT ;
    USE SIGNAL ;
    PORT
      LAYER M1 ;
        RECT 0.0570 0.0210 0.0690 0.0330 ;
    END
  END A2
  PIN A1
    DIRECTION INPUT ;
    USE SIGNAL ;
    PORT
      LAYER M1 ;
        RECT 0.0150 0.0210 0.0270 0.0330 ;
    END
  END A1
END NAND2_X1

MACRO NAND2_X2
  CLASS CORE ;
  FOREIGN NAND2_X2 0 0 ;
  ORIGIN 0.0000 0.0000 ;
  SIZE 0.2100 BY 0.0720 ;
  SYMMETRY X Y ;
  SITE i3d_16A ;
  PIN VSS
    DIRECTION INOUT ;
    USE GROUND ;
    PORT
      LAYER BPR ;
        RECT -0.0160 -0.0135 0.2260 0.0135 ;
    END
  END VSS
  PIN VDD
    DIRECTION INOUT ;
    USE POWER ;
    PORT
      LAYER BPR ;
        RECT -0.0160 0.0585 0.2260 0.0855 ;
    END
  END VDD
  PIN A2
    DIRECTION INPUT ;
    USE SIGNAL ;
    PORT
      LAYER M1 ;
        RECT 0.1410 0.0210 0.1530 0.0690 ;
    END
  END A2
  PIN ZN
    DIRECTION OUTPUT ;
    USE SIGNAL ;
    PORT
      LAYER M1 ;
        RECT 0.0990 0.0210 0.1110 0.0510 ;
    END
  END ZN
  PIN A1
    DIRECTION INPUT ;
    USE SIGNAL ;
    PORT
      LAYER M1 ;
        RECT 0.1830 0.0030 0.1950 0.0510 ;
    END
  END A1
END NAND2_X2

MACRO NAND2_X4
  CLASS CORE ;
  FOREIGN NAND2_X4 0 0 ;
  ORIGIN 0.0000 0.0000 ;
  SIZE 0.3780 BY 0.0720 ;
  SYMMETRY X Y ;
  SITE i3d_16A ;
  PIN VDD
    DIRECTION INOUT ;
    USE POWER ;
    PORT
      LAYER BPR ;
        RECT -0.0160 0.0585 0.3940 0.0855 ;
    END
  END VDD
  PIN VSS
    DIRECTION INOUT ;
    USE GROUND ;
    PORT
      LAYER BPR ;
        RECT -0.0160 -0.0135 0.3940 0.0135 ;
    END
  END VSS
  PIN A2
    DIRECTION INPUT ;
    USE SIGNAL ;
    PORT
      LAYER M1 ;
        RECT 0.2670 0.0450 0.2790 0.0685 ;
    END
  END A2
  PIN ZN
    DIRECTION OUTPUT ;
    USE SIGNAL ;
    PORT
      LAYER M1 ;
        RECT 0.2250 0.0215 0.2370 0.0505 ;
        RECT 0.3090 0.0215 0.3210 0.0510 ;
    END
  END ZN
  PIN A1
    DIRECTION INPUT ;
    USE SIGNAL ;
    PORT
      LAYER M1 ;
        RECT 0.0570 0.0395 0.0690 0.0685 ;
    END
  END A1
END NAND2_X4

MACRO NAND3_X1
  CLASS CORE ;
  FOREIGN NAND3_X1 0 0 ;
  ORIGIN 0.0000 0.0000 ;
  SIZE 0.1680 BY 0.0720 ;
  SYMMETRY X Y ;
  SITE i3d_16A ;
  PIN VSS
    DIRECTION INOUT ;
    USE GROUND ;
    PORT
      LAYER BPR ;
        RECT -0.0160 -0.0135 0.1840 0.0135 ;
    END
  END VSS
  PIN VDD
    DIRECTION INOUT ;
    USE POWER ;
    PORT
      LAYER BPR ;
        RECT -0.0160 0.0585 0.1840 0.0855 ;
    END
  END VDD
  PIN A1
    DIRECTION INPUT ;
    USE SIGNAL ;
    PORT
      LAYER M1 ;
        RECT 0.0150 0.0210 0.0270 0.0510 ;
    END
  END A1
  PIN A2
    DIRECTION INPUT ;
    USE SIGNAL ;
    PORT
      LAYER M1 ;
        RECT 0.0570 0.0210 0.0690 0.0510 ;
    END
  END A2
  PIN A3
    DIRECTION INPUT ;
    USE SIGNAL ;
    PORT
      LAYER M1 ;
        RECT 0.1410 0.0385 0.1530 0.0685 ;
    END
  END A3
  PIN ZN
    DIRECTION OUTPUT ;
    USE SIGNAL ;
    PORT
      LAYER M1 ;
        RECT 0.0990 0.0210 0.1110 0.0510 ;
    END
  END ZN
END NAND3_X1

MACRO NAND4_X1
  CLASS CORE ;
  FOREIGN NAND4_X1 0 0 ;
  ORIGIN 0.0000 0.0000 ;
  SIZE 0.2520 BY 0.0720 ;
  SYMMETRY X Y ;
  SITE i3d_16A ;
  PIN VDD
    DIRECTION INOUT ;
    USE POWER ;
    PORT
      LAYER BPR ;
        RECT -0.0160 0.0585 0.2680 0.0855 ;
    END
  END VDD
  PIN VSS
    DIRECTION INOUT ;
    USE GROUND ;
    PORT
      LAYER BPR ;
        RECT -0.0160 -0.0135 0.2680 0.0135 ;
    END
  END VSS
  PIN ZN
    DIRECTION OUTPUT ;
    USE SIGNAL ;
    PORT
      LAYER M1 ;
        RECT 0.0570 0.0215 0.0690 0.0515 ;
    END
  END ZN
  PIN A2
    DIRECTION INPUT ;
    USE SIGNAL ;
    PORT
      LAYER M1 ;
        RECT 0.0990 0.0215 0.1110 0.0515 ;
    END
  END A2
  PIN A3
    DIRECTION INPUT ;
    USE SIGNAL ;
    PORT
      LAYER M1 ;
        RECT 0.1410 0.0215 0.1530 0.0515 ;
    END
  END A3
  PIN A1
    DIRECTION INPUT ;
    USE SIGNAL ;
    PORT
      LAYER M1 ;
        RECT 0.0150 0.0210 0.0270 0.0510 ;
    END
  END A1
  PIN A4
    DIRECTION INPUT ;
    USE SIGNAL ;
    PORT
      LAYER M1 ;
        RECT 0.1830 0.0215 0.1950 0.0515 ;
    END
  END A4
END NAND4_X1

MACRO NOR2_X1
  CLASS CORE ;
  FOREIGN NOR2_X1 0 0 ;
  ORIGIN 0.0000 0.0000 ;
  SIZE 0.1260 BY 0.0720 ;
  SYMMETRY X Y ;
  SITE i3d_16A ;
  PIN VDD
    DIRECTION INOUT ;
    USE POWER ;
    PORT
      LAYER BPR ;
        RECT -0.0160 0.0585 0.1420 0.0855 ;
    END
  END VDD
  PIN VSS
    DIRECTION INOUT ;
    USE GROUND ;
    PORT
      LAYER BPR ;
        RECT -0.0160 -0.0135 0.1420 0.0135 ;
    END
  END VSS
  PIN A2
    DIRECTION INPUT ;
    USE SIGNAL ;
    PORT
      LAYER M1 ;
        RECT 0.0570 0.0390 0.0690 0.0510 ;
    END
  END A2
  PIN ZN
    DIRECTION OUTPUT ;
    USE SIGNAL ;
    PORT
      LAYER M1 ;
        RECT 0.0990 0.0210 0.1110 0.0510 ;
    END
  END ZN
  PIN A1
    DIRECTION INPUT ;
    USE SIGNAL ;
    PORT
      LAYER M1 ;
        RECT 0.0150 0.0390 0.0270 0.0515 ;
    END
  END A1
END NOR2_X1

MACRO NOR2_X2
  CLASS CORE ;
  FOREIGN NOR2_X2 0 0 ;
  ORIGIN 0.0000 0.0000 ;
  SIZE 0.2100 BY 0.0720 ;
  SYMMETRY X Y ;
  SITE i3d_16A ;
  PIN VSS
    DIRECTION INOUT ;
    USE GROUND ;
    PORT
      LAYER BPR ;
        RECT -0.0160 -0.0135 0.2260 0.0135 ;
    END
  END VSS
  PIN VDD
    DIRECTION INOUT ;
    USE POWER ;
    PORT
      LAYER BPR ;
        RECT -0.0160 0.0585 0.2260 0.0855 ;
    END
  END VDD
  PIN A2
    DIRECTION INPUT ;
    USE SIGNAL ;
    PORT
      LAYER M1 ;
        RECT 0.0570 0.0035 0.0690 0.0505 ;
    END
  END A2
  PIN ZN
    DIRECTION OUTPUT ;
    USE SIGNAL ;
    PORT
      LAYER M1 ;
        RECT 0.0990 0.0215 0.1110 0.0505 ;
    END
  END ZN
  PIN A1
    DIRECTION INPUT ;
    USE SIGNAL ;
    PORT
      LAYER M1 ;
        RECT 0.0150 0.0215 0.0270 0.0685 ;
    END
  END A1
END NOR2_X2

MACRO NOR2_X4
  CLASS CORE ;
  FOREIGN NOR2_X4 0 0 ;
  ORIGIN 0.0000 0.0000 ;
  SIZE 0.3780 BY 0.0720 ;
  SYMMETRY X Y ;
  SITE i3d_16A ;
  PIN VDD
    DIRECTION INOUT ;
    USE POWER ;
    PORT
      LAYER BPR ;
        RECT -0.0160 0.0585 0.3940 0.0855 ;
    END
  END VDD
  PIN VSS
    DIRECTION INOUT ;
    USE GROUND ;
    PORT
      LAYER BPR ;
        RECT -0.0160 -0.0135 0.3940 0.0135 ;
    END
  END VSS
  PIN A1
    DIRECTION INPUT ;
    USE SIGNAL ;
    PORT
      LAYER M1 ;
        RECT 0.0150 0.0395 0.0270 0.0505 ;
    END
  END A1
  PIN ZN
    DIRECTION OUTPUT ;
    USE SIGNAL ;
    PORT
      LAYER M1 ;
        RECT 0.3090 0.0215 0.3210 0.0505 ;
    END
  END ZN
  PIN A2
    DIRECTION INPUT ;
    USE SIGNAL ;
    PORT
      LAYER M1 ;
        RECT 0.3510 0.0035 0.3630 0.0145 ;
    END
  END A2
  OBS
    LAYER M1 ;
      RECT 0.2255 0.0215 0.2375 0.0505 ;
  END
END NOR2_X4

MACRO NOR3_X1
  CLASS CORE ;
  FOREIGN NOR3_X1 0 0 ;
  ORIGIN 0.0000 0.0000 ;
  SIZE 0.1680 BY 0.0720 ;
  SYMMETRY X Y ;
  SITE i3d_16A ;
  PIN VSS
    DIRECTION INOUT ;
    USE GROUND ;
    PORT
      LAYER BPR ;
        RECT -0.0160 -0.0135 0.1840 0.0135 ;
    END
  END VSS
  PIN VDD
    DIRECTION INOUT ;
    USE POWER ;
    PORT
      LAYER BPR ;
        RECT -0.0160 0.0585 0.1840 0.0855 ;
    END
  END VDD
  PIN A3
    DIRECTION INPUT ;
    USE SIGNAL ;
    PORT
      LAYER M1 ;
        RECT 0.1410 0.0390 0.1530 0.0510 ;
    END
  END A3
  PIN ZN
    DIRECTION OUTPUT ;
    USE SIGNAL ;
    PORT
      LAYER M1 ;
        RECT 0.0570 0.0215 0.0690 0.0510 ;
    END
  END ZN
  PIN A2
    DIRECTION INPUT ;
    USE SIGNAL ;
    PORT
      LAYER M1 ;
        RECT 0.0990 0.0390 0.1110 0.0510 ;
    END
  END A2
  PIN A1
    DIRECTION INPUT ;
    USE SIGNAL ;
    PORT
      LAYER M1 ;
        RECT 0.0150 0.0215 0.0270 0.0335 ;
    END
  END A1
END NOR3_X1

MACRO NOR4_X1
  CLASS CORE ;
  FOREIGN NOR4_X1 0 0 ;
  ORIGIN 0.0000 0.0000 ;
  SIZE 0.2100 BY 0.0720 ;
  SYMMETRY X Y ;
  SITE i3d_16A ;
  PIN VDD
    DIRECTION INOUT ;
    USE POWER ;
    PORT
      LAYER BPR ;
        RECT -0.0160 0.0585 0.2260 0.0855 ;
    END
  END VDD
  PIN VSS
    DIRECTION INOUT ;
    USE GROUND ;
    PORT
      LAYER BPR ;
        RECT -0.0160 -0.0135 0.2260 0.0135 ;
    END
  END VSS
  PIN ZN
    DIRECTION OUTPUT ;
    USE SIGNAL ;
    PORT
      LAYER M1 ;
        RECT 0.1410 0.0215 0.1530 0.0510 ;
    END
  END ZN
  PIN A4
    DIRECTION INPUT ;
    USE SIGNAL ;
    PORT
      LAYER M1 ;
        RECT 0.0150 0.0215 0.0270 0.0510 ;
    END
  END A4
  PIN A2
    DIRECTION INPUT ;
    USE SIGNAL ;
    PORT
      LAYER M1 ;
        RECT 0.0990 0.0390 0.1110 0.0685 ;
    END
  END A2
  PIN A3
    DIRECTION INPUT ;
    USE SIGNAL ;
    PORT
      LAYER M1 ;
        RECT 0.0570 0.0390 0.0690 0.0685 ;
    END
  END A3
  PIN A1
    DIRECTION INPUT ;
    USE SIGNAL ;
    PORT
      LAYER M1 ;
        RECT 0.1830 0.0215 0.1950 0.0505 ;
    END
  END A1
END NOR4_X1

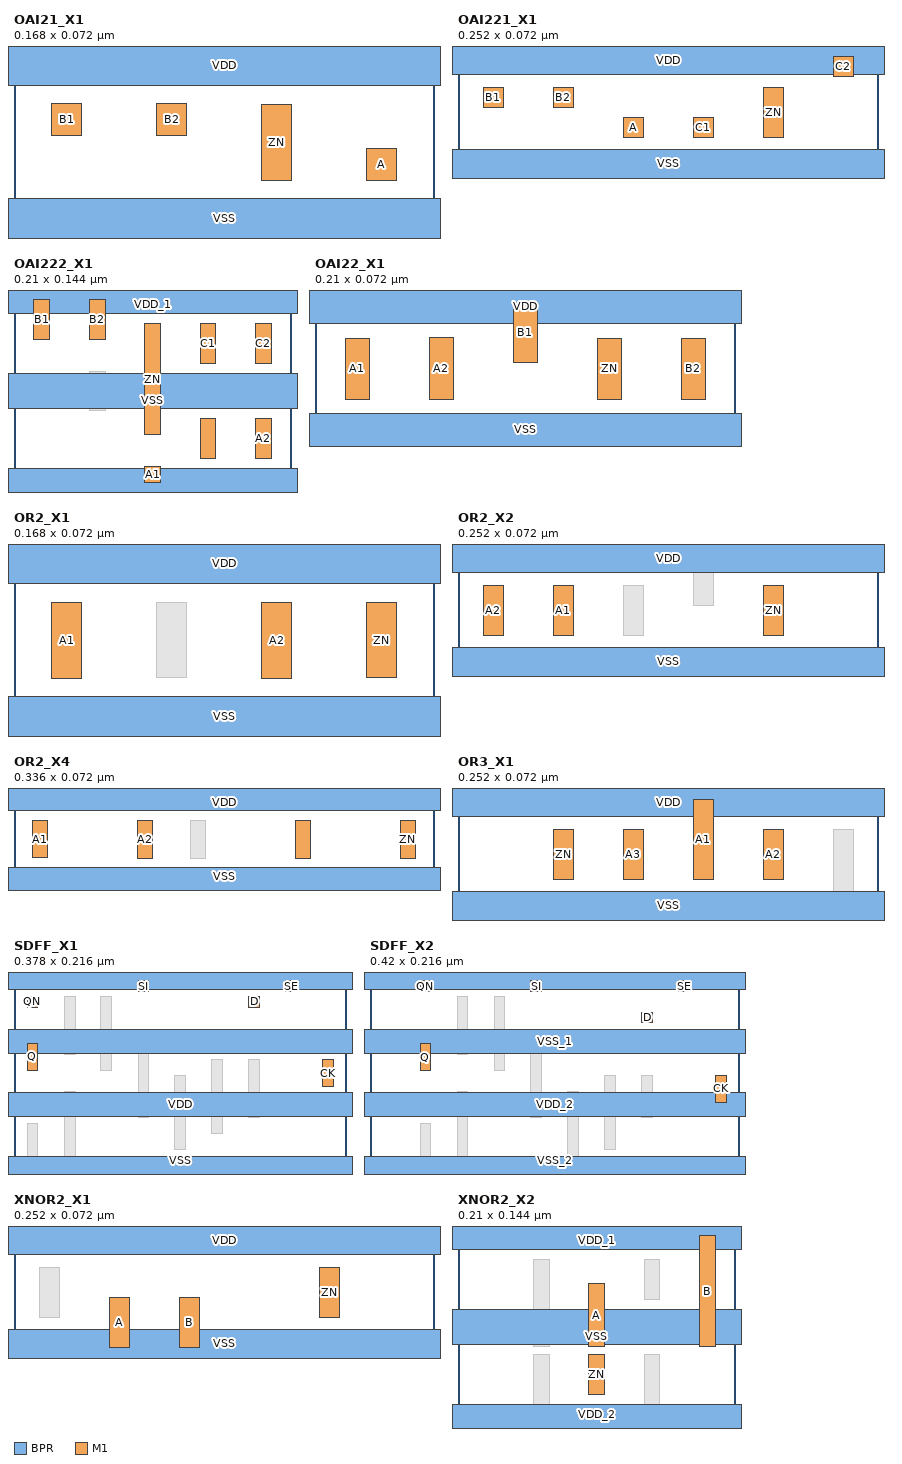
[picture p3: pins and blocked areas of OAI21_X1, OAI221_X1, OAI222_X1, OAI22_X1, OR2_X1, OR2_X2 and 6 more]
MACRO OAI21_X1
  CLASS CORE ;
  FOREIGN OAI21_X1 0 0 ;
  ORIGIN 0.0000 0.0000 ;
  SIZE 0.1680 BY 0.0720 ;
  SYMMETRY X Y ;
  SITE i3d_16A ;
  PIN VDD
    DIRECTION INOUT ;
    USE POWER ;
    PORT
      LAYER BPR ;
        RECT -0.0160 0.0585 0.1840 0.0855 ;
    END
  END VDD
  PIN VSS
    DIRECTION INOUT ;
    USE GROUND ;
    PORT
      LAYER BPR ;
        RECT -0.0160 -0.0135 0.1840 0.0135 ;
    END
  END VSS
  PIN B1
    DIRECTION INPUT ;
    USE SIGNAL ;
    PORT
      LAYER M1 ;
        RECT 0.0150 0.0385 0.0270 0.0515 ;
    END
  END B1
  PIN A
    DIRECTION INPUT ;
    USE SIGNAL ;
    PORT
      LAYER M1 ;
        RECT 0.1410 0.0205 0.1530 0.0335 ;
    END
  END A
  PIN ZN
    DIRECTION OUTPUT ;
    USE SIGNAL ;
    PORT
      LAYER M1 ;
        RECT 0.0990 0.0205 0.1110 0.0510 ;
    END
  END ZN
  PIN B2
    DIRECTION INPUT ;
    USE SIGNAL ;
    PORT
      LAYER M1 ;
        RECT 0.0570 0.0385 0.0690 0.0515 ;
    END
  END B2
END OAI21_X1

MACRO OAI221_X1
  CLASS CORE ;
  FOREIGN OAI221_X1 0 0 ;
  ORIGIN 0.0000 0.0000 ;
  SIZE 0.2520 BY 0.0720 ;
  SYMMETRY X Y ;
  SITE i3d_16A ;
  PIN VSS
    DIRECTION INOUT ;
    USE GROUND ;
    PORT
      LAYER BPR ;
        RECT -0.0160 -0.0135 0.2680 0.0135 ;
    END
  END VSS
  PIN VDD
    DIRECTION INOUT ;
    USE POWER ;
    PORT
      LAYER BPR ;
        RECT -0.0160 0.0585 0.2680 0.0855 ;
    END
  END VDD
  PIN B1
    DIRECTION INPUT ;
    USE SIGNAL ;
    PORT
      LAYER M1 ;
        RECT 0.0150 0.0390 0.0270 0.0510 ;
    END
  END B1
  PIN A
    DIRECTION INPUT ;
    USE SIGNAL ;
    PORT
      LAYER M1 ;
        RECT 0.0990 0.0210 0.1110 0.0330 ;
    END
  END A
  PIN ZN
    DIRECTION OUTPUT ;
    USE SIGNAL ;
    PORT
      LAYER M1 ;
        RECT 0.1830 0.0205 0.1950 0.0510 ;
    END
  END ZN
  PIN B2
    DIRECTION INPUT ;
    USE SIGNAL ;
    PORT
      LAYER M1 ;
        RECT 0.0570 0.0390 0.0690 0.0510 ;
    END
  END B2
  PIN C2
    DIRECTION INPUT ;
    USE SIGNAL ;
    PORT
      LAYER M1 ;
        RECT 0.2250 0.0570 0.2370 0.0690 ;
    END
  END C2
  PIN C1
    DIRECTION INPUT ;
    USE SIGNAL ;
    PORT
      LAYER M1 ;
        RECT 0.1410 0.0210 0.1530 0.0330 ;
    END
  END C1
END OAI221_X1

MACRO OAI222_X1
  CLASS CORE ;
  FOREIGN OAI222_X1 0 0 ;
  ORIGIN 0.0000 0.0000 ;
  SIZE 0.2100 BY 0.1440 ;
  SYMMETRY X Y ;
  SITE i3d_16A ;
  PIN VDD_2
    DIRECTION INOUT ;
    USE POWER ;
    PORT
      LAYER BPR ;
        RECT -0.0160 -0.0135 0.2260 0.0135 ;
    END
  END VDD_2
  PIN VSS
    DIRECTION INOUT ;
    USE GROUND ;
    PORT
      LAYER BPR ;
        RECT -0.0160 0.0585 0.2260 0.0855 ;
    END
  END VSS
  PIN VDD_1
    DIRECTION INOUT ;
    USE POWER ;
    PORT
      LAYER BPR ;
        RECT -0.0160 0.1305 0.2260 0.1575 ;
    END
  END VDD_1
  PIN C2
    DIRECTION INPUT ;
    USE SIGNAL ;
    PORT
      LAYER M1 ;
        RECT 0.1830 0.0930 0.1950 0.1230 ;
    END
  END C2
  PIN A2
    DIRECTION INPUT ;
    USE SIGNAL ;
    PORT
      LAYER M1 ;
        RECT 0.1830 0.0210 0.1950 0.0510 ;
    END
  END A2
  PIN ZN
    DIRECTION OUTPUT ;
    USE SIGNAL ;
    PORT
      LAYER M1 ;
        RECT 0.0990 0.0390 0.1110 0.1230 ;
        RECT 0.1410 0.0210 0.1530 0.0510 ;
    END
  END ZN
  PIN C1
    DIRECTION INPUT ;
    USE SIGNAL ;
    PORT
      LAYER M1 ;
        RECT 0.1410 0.0930 0.1530 0.1230 ;
    END
  END C1
  PIN A1
    DIRECTION INPUT ;
    USE SIGNAL ;
    PORT
      LAYER M1 ;
        RECT 0.0990 0.0030 0.1110 0.0150 ;
    END
  END A1
  PIN B2
    DIRECTION INPUT ;
    USE SIGNAL ;
    PORT
      LAYER M1 ;
        RECT 0.0570 0.1110 0.0690 0.1410 ;
    END
  END B2
  PIN B1
    DIRECTION INPUT ;
    USE SIGNAL ;
    PORT
      LAYER M1 ;
        RECT 0.0150 0.1110 0.0270 0.1410 ;
    END
  END B1
  OBS
    LAYER M1 ;
      RECT 0.0570 0.0570 0.0690 0.0870 ;
  END
END OAI222_X1

MACRO OAI22_X1
  CLASS CORE ;
  FOREIGN OAI22_X1 0 0 ;
  ORIGIN 0.0000 0.0000 ;
  SIZE 0.2100 BY 0.0720 ;
  SYMMETRY X Y ;
  SITE i3d_16A ;
  PIN VSS
    DIRECTION INOUT ;
    USE GROUND ;
    PORT
      LAYER BPR ;
        RECT -0.0160 -0.0135 0.2260 0.0135 ;
    END
  END VSS
  PIN VDD
    DIRECTION INOUT ;
    USE POWER ;
    PORT
      LAYER BPR ;
        RECT -0.0160 0.0585 0.2260 0.0855 ;
    END
  END VDD
  PIN ZN
    DIRECTION OUTPUT ;
    USE SIGNAL ;
    PORT
      LAYER M1 ;
        RECT 0.1410 0.0205 0.1530 0.0510 ;
    END
  END ZN
  PIN B2
    DIRECTION INPUT ;
    USE SIGNAL ;
    PORT
      LAYER M1 ;
        RECT 0.1830 0.0205 0.1950 0.0510 ;
    END
  END B2
  PIN A1
    DIRECTION INPUT ;
    USE SIGNAL ;
    PORT
      LAYER M1 ;
        RECT 0.0150 0.0205 0.0270 0.0510 ;
    END
  END A1
  PIN A2
    DIRECTION INPUT ;
    USE SIGNAL ;
    PORT
      LAYER M1 ;
        RECT 0.0570 0.0205 0.0690 0.0515 ;
    END
  END A2
  PIN B1
    DIRECTION INPUT ;
    USE SIGNAL ;
    PORT
      LAYER M1 ;
        RECT 0.0990 0.0390 0.1110 0.0690 ;
    END
  END B1
END OAI22_X1

MACRO OR2_X1
  CLASS CORE ;
  FOREIGN OR2_X1 0 0 ;
  ORIGIN 0.0000 0.0000 ;
  SIZE 0.1680 BY 0.0720 ;
  SYMMETRY X Y ;
  SITE i3d_16A ;
  PIN VSS
    DIRECTION INOUT ;
    USE GROUND ;
    PORT
      LAYER BPR ;
        RECT -0.0160 -0.0135 0.1840 0.0135 ;
    END
  END VSS
  PIN VDD
    DIRECTION INOUT ;
    USE POWER ;
    PORT
      LAYER BPR ;
        RECT -0.0160 0.0585 0.1840 0.0855 ;
    END
  END VDD
  PIN A2
    DIRECTION INPUT ;
    USE SIGNAL ;
    PORT
      LAYER M1 ;
        RECT 0.0990 0.0205 0.1110 0.0510 ;
    END
  END A2
  PIN A1
    DIRECTION INPUT ;
    USE SIGNAL ;
    PORT
      LAYER M1 ;
        RECT 0.0150 0.0205 0.0270 0.0510 ;
    END
  END A1
  PIN ZN
    DIRECTION OUTPUT ;
    USE SIGNAL ;
    PORT
      LAYER M1 ;
        RECT 0.1410 0.0210 0.1530 0.0510 ;
    END
  END ZN
  OBS
    LAYER M1 ;
      RECT 0.0570 0.0210 0.0690 0.0510 ;
  END
END OR2_X1

MACRO OR2_X2
  CLASS CORE ;
  FOREIGN OR2_X2 0 0 ;
  ORIGIN 0.0000 0.0000 ;
  SIZE 0.2520 BY 0.0720 ;
  SYMMETRY X Y ;
  SITE i3d_16A ;
  PIN VDD
    DIRECTION INOUT ;
    USE POWER ;
    PORT
      LAYER BPR ;
        RECT -0.0160 0.0585 0.2680 0.0855 ;
    END
  END VDD
  PIN VSS
    DIRECTION INOUT ;
    USE GROUND ;
    PORT
      LAYER BPR ;
        RECT -0.0160 -0.0135 0.2680 0.0135 ;
    END
  END VSS
  PIN A2
    DIRECTION INPUT ;
    USE SIGNAL ;
    PORT
      LAYER M1 ;
        RECT 0.0150 0.0210 0.0270 0.0510 ;
    END
  END A2
  PIN ZN
    DIRECTION OUTPUT ;
    USE SIGNAL ;
    PORT
      LAYER M1 ;
        RECT 0.1830 0.0205 0.1950 0.0510 ;
    END
  END ZN
  PIN A1
    DIRECTION INPUT ;
    USE SIGNAL ;
    PORT
      LAYER M1 ;
        RECT 0.0570 0.0210 0.0690 0.0510 ;
    END
  END A1
  OBS
    LAYER M1 ;
      RECT 0.1410 0.0390 0.1530 0.0695 ;
      RECT 0.0990 0.0205 0.1110 0.0510 ;
  END
END OR2_X2

MACRO OR2_X4
  CLASS CORE ;
  FOREIGN OR2_X4 0 0 ;
  ORIGIN 0.0000 0.0000 ;
  SIZE 0.3360 BY 0.0720 ;
  SYMMETRY X Y ;
  SITE i3d_16A ;
  PIN VDD
    DIRECTION INOUT ;
    USE POWER ;
    PORT
      LAYER BPR ;
        RECT -0.0160 0.0585 0.3520 0.0855 ;
    END
  END VDD
  PIN VSS
    DIRECTION INOUT ;
    USE GROUND ;
    PORT
      LAYER BPR ;
        RECT -0.0160 -0.0135 0.3520 0.0135 ;
    END
  END VSS
  PIN ZN
    DIRECTION OUTPUT ;
    USE SIGNAL ;
    PORT
      LAYER M1 ;
        RECT 0.2250 0.0205 0.2370 0.0510 ;
        RECT 0.3090 0.0205 0.3210 0.0510 ;
    END
  END ZN
  PIN A2
    DIRECTION INPUT ;
    USE SIGNAL ;
    PORT
      LAYER M1 ;
        RECT 0.0990 0.0205 0.1110 0.0510 ;
    END
  END A2
  PIN A1
    DIRECTION INPUT ;
    USE SIGNAL ;
    PORT
      LAYER M1 ;
        RECT 0.0150 0.0210 0.0270 0.0510 ;
    END
  END A1
  OBS
    LAYER M1 ;
      RECT 0.1410 0.0205 0.1530 0.0510 ;
  END
END OR2_X4

MACRO OR3_X1
  CLASS CORE ;
  FOREIGN OR3_X1 0 0 ;
  ORIGIN 0.0000 0.0000 ;
  SIZE 0.2520 BY 0.0720 ;
  SYMMETRY X Y ;
  SITE i3d_16A ;
  PIN VSS
    DIRECTION INOUT ;
    USE GROUND ;
    PORT
      LAYER BPR ;
        RECT -0.0160 -0.0135 0.2680 0.0135 ;
    END
  END VSS
  PIN VDD
    DIRECTION INOUT ;
    USE POWER ;
    PORT
      LAYER BPR ;
        RECT -0.0160 0.0585 0.2680 0.0855 ;
    END
  END VDD
  PIN A2
    DIRECTION INPUT ;
    USE SIGNAL ;
    PORT
      LAYER M1 ;
        RECT 0.1830 0.0210 0.1950 0.0510 ;
    END
  END A2
  PIN ZN
    DIRECTION OUTPUT ;
    USE SIGNAL ;
    PORT
      LAYER M1 ;
        RECT 0.0570 0.0210 0.0690 0.0510 ;
    END
  END ZN
  PIN A1
    DIRECTION INPUT ;
    USE SIGNAL ;
    PORT
      LAYER M1 ;
        RECT 0.1410 0.0210 0.1530 0.0690 ;
    END
  END A1
  PIN A3
    DIRECTION INPUT ;
    USE SIGNAL ;
    PORT
      LAYER M1 ;
        RECT 0.0990 0.0210 0.1110 0.0510 ;
    END
  END A3
  OBS
    LAYER M1 ;
      RECT 0.2250 0.0030 0.2370 0.0510 ;
  END
END OR3_X1

MACRO SDFF_X1
  CLASS CORE ;
  FOREIGN SDFF_X1 0 0 ;
  ORIGIN 0.0000 0.0000 ;
  SIZE 0.3780 BY 0.2160 ;
  SYMMETRY X Y ;
  SITE i3d_16A ;
  PIN VDD
    DIRECTION INOUT ;
    USE POWER ;
    PORT
      LAYER BPR ;
        RECT -0.0160 0.2025 0.3940 0.2295 ;
        RECT -0.0160 0.0585 0.3940 0.0855 ;
    END
  END VDD
  PIN VSS
    DIRECTION INOUT ;
    USE GROUND ;
    PORT
      LAYER BPR ;
        RECT -0.0160 -0.0135 0.3940 0.0135 ;
        RECT -0.0160 0.1305 0.3940 0.1575 ;
    END
  END VSS
  PIN SE
    DIRECTION INPUT ;
    USE SIGNAL ;
    PORT
      LAYER M1 ;
        RECT 0.3090 0.2010 0.3210 0.2135 ;
    END
  END SE
  PIN CK
    DIRECTION INPUT ;
    USE CLOCK ;
    PORT
      LAYER M1 ;
        RECT 0.3510 0.0930 0.3630 0.1230 ;
    END
  END CK
  PIN Q
    DIRECTION OUTPUT ;
    USE SIGNAL ;
    PORT
      LAYER M1 ;
        RECT 0.0150 0.1110 0.0270 0.1415 ;
    END
  END Q
  PIN SI
    DIRECTION INPUT ;
    USE SIGNAL ;
    PORT
      LAYER M1 ;
        RECT 0.1410 0.2010 0.1530 0.2130 ;
    END
  END SI
  PIN QN
    DIRECTION OUTPUT ;
    USE SIGNAL ;
    PORT
      LAYER M1 ;
        RECT 0.0150 0.1830 0.0270 0.1950 ;
    END
  END QN
  PIN D
    DIRECTION INPUT ;
    USE SIGNAL ;
    PORT
      LAYER M1 ;
        RECT 0.2670 0.1825 0.2790 0.1950 ;
    END
  END D
  OBS
    LAYER M1 ;
      RECT 0.0150 0.0030 0.0270 0.0510 ;
      RECT 0.0570 0.0030 0.0695 0.0870 ;
      RECT 0.1830 0.0210 0.1955 0.1050 ;
      RECT 0.2250 0.0390 0.2370 0.1230 ;
      RECT 0.2670 0.0570 0.2790 0.1230 ;
      RECT 0.1410 0.0570 0.1530 0.1410 ;
      RECT 0.0570 0.1290 0.0695 0.1955 ;
      RECT 0.0985 0.1110 0.1110 0.1955 ;
  END
END SDFF_X1

MACRO SDFF_X2
  CLASS CORE ;
  FOREIGN SDFF_X2 0 0 ;
  ORIGIN 0.0000 0.0000 ;
  SIZE 0.4200 BY 0.2160 ;
  SYMMETRY X Y ;
  SITE i3d_16A ;
  PIN VSS_2
    DIRECTION INOUT ;
    USE GROUND ;
    PORT
      LAYER BPR ;
        RECT -0.0160 -0.0135 0.4350 0.0135 ;
    END
  END VSS_2
  PIN VSS_1
    DIRECTION INOUT ;
    USE GROUND ;
    PORT
      LAYER BPR ;
        RECT -0.0160 0.1305 0.4350 0.1575 ;
        RECT -0.0160 0.1305 0.4350 0.1575 ;
    END
  END VSS_1
  PIN VDD_2
    DIRECTION INOUT ;
    USE POWER ;
    PORT
      LAYER BPR ;
        RECT -0.0160 0.0585 0.4350 0.0855 ;
        RECT -0.0160 0.0585 0.4350 0.0855 ;
        RECT -0.0160 0.0585 0.4350 0.0855 ;
    END
  END VDD_2
  PIN VDD_1
    DIRECTION INOUT ;
    USE POWER ;
    PORT
      LAYER BPR ;
        RECT -0.0160 0.2025 0.4350 0.2295 ;
    END
  END VDD_1
  PIN SE
    DIRECTION INPUT ;
    USE SIGNAL ;
    PORT
      LAYER M1 ;
        RECT 0.3510 0.2010 0.3630 0.2130 ;
    END
  END SE
  PIN QN
    DIRECTION OUTPUT ;
    USE SIGNAL ;
    PORT
      LAYER M1 ;
        RECT 0.0570 0.2010 0.0690 0.2130 ;
    END
  END QN
  PIN Q
    DIRECTION OUTPUT ;
    USE SIGNAL ;
    PORT
      LAYER M1 ;
        RECT 0.0570 0.1110 0.0690 0.1410 ;
    END
  END Q
  PIN CK
    DIRECTION INPUT ;
    USE CLOCK ;
    PORT
      LAYER M1 ;
        RECT 0.3930 0.0750 0.4050 0.1050 ;
    END
  END CK
  PIN SI
    DIRECTION INPUT ;
    USE SIGNAL ;
    PORT
      LAYER M1 ;
        RECT 0.1830 0.2010 0.1950 0.2130 ;
    END
  END SI
  PIN D
    DIRECTION INPUT ;
    USE SIGNAL ;
    PORT
      LAYER M1 ;
        RECT 0.3090 0.1650 0.3210 0.1770 ;
    END
  END D
  OBS
    LAYER M1 ;
      RECT 0.3090 0.0570 0.3210 0.1050 ;
      RECT 0.2670 0.0210 0.2790 0.1050 ;
      RECT 0.2250 0.0030 0.2370 0.0870 ;
      RECT 0.1830 0.0570 0.1950 0.1410 ;
      RECT 0.1410 0.1110 0.1530 0.1950 ;
      RECT 0.0990 0.0030 0.1110 0.0870 ;
      RECT 0.0570 0.0030 0.0690 0.0510 ;
      RECT 0.0990 0.1290 0.1110 0.1950 ;
  END
END SDFF_X2

MACRO XNOR2_X1
  CLASS CORE ;
  FOREIGN XNOR2_X1 0 0 ;
  ORIGIN 0.0000 0.0000 ;
  SIZE 0.2520 BY 0.0720 ;
  SYMMETRY X Y ;
  SITE i3d_16A ;
  PIN VSS
    DIRECTION INOUT ;
    USE GROUND ;
    PORT
      LAYER BPR ;
        RECT -0.0160 -0.0135 0.2680 0.0135 ;
    END
  END VSS
  PIN VDD
    DIRECTION INOUT ;
    USE POWER ;
    PORT
      LAYER BPR ;
        RECT -0.0160 0.0585 0.2680 0.0855 ;
    END
  END VDD
  PIN B
    DIRECTION INPUT ;
    USE SIGNAL ;
    PORT
      LAYER M1 ;
        RECT 0.0990 0.0030 0.1110 0.0330 ;
    END
  END B
  PIN ZN
    DIRECTION OUTPUT ;
    USE SIGNAL ;
    PORT
      LAYER M1 ;
        RECT 0.1830 0.0205 0.1950 0.0510 ;
    END
  END ZN
  PIN A
    DIRECTION INPUT ;
    USE SIGNAL ;
    PORT
      LAYER M1 ;
        RECT 0.0570 0.0030 0.0690 0.0330 ;
    END
  END A
  OBS
    LAYER M1 ;
      RECT 0.0150 0.0210 0.0270 0.0510 ;
  END
END XNOR2_X1

MACRO XNOR2_X2
  CLASS CORE ;
  FOREIGN XNOR2_X2 0 0 ;
  ORIGIN 0.0000 0.0000 ;
  SIZE 0.2100 BY 0.1440 ;
  SYMMETRY X Y ;
  SITE i3d_16A ;
  PIN VDD_2
    DIRECTION INOUT ;
    USE POWER ;
    PORT
      LAYER BPR ;
        RECT -0.0160 -0.0135 0.2260 0.0135 ;
    END
  END VDD_2
  PIN VSS
    DIRECTION INOUT ;
    USE GROUND ;
    PORT
      LAYER BPR ;
        RECT -0.0160 0.0585 0.2260 0.0855 ;
    END
  END VSS
  PIN VDD_1
    DIRECTION INOUT ;
    USE POWER ;
    PORT
      LAYER BPR ;
        RECT -0.0160 0.1305 0.2260 0.1575 ;
    END
  END VDD_1
  PIN B
    DIRECTION INPUT ;
    USE SIGNAL ;
    PORT
      LAYER M1 ;
        RECT 0.1830 0.0570 0.1950 0.1410 ;
    END
  END B
  PIN ZN
    DIRECTION OUTPUT ;
    USE SIGNAL ;
    PORT
      LAYER M1 ;
        RECT 0.0990 0.0210 0.1110 0.0510 ;
    END
  END ZN
  PIN A
    DIRECTION INPUT ;
    USE SIGNAL ;
    PORT
      LAYER M1 ;
        RECT 0.0990 0.0570 0.1110 0.1050 ;
    END
  END A
  OBS
    LAYER M1 ;
      RECT 0.1410 0.0030 0.1530 0.0510 ;
      RECT 0.0570 0.0030 0.0690 0.0510 ;
      RECT 0.0570 0.0570 0.0690 0.1230 ;
      RECT 0.1410 0.0925 0.1530 0.1230 ;
  END
END XNOR2_X2

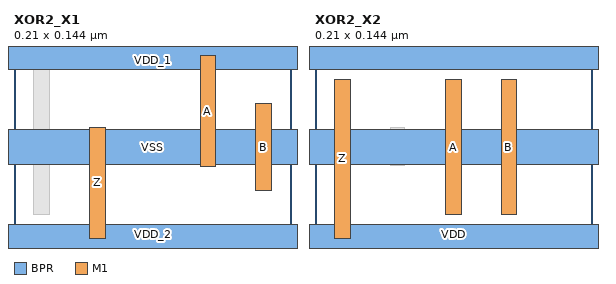
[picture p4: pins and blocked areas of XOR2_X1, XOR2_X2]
MACRO XOR2_X1
  CLASS CORE ;
  FOREIGN XOR2_X1 0 0 ;
  ORIGIN 0.0000 0.0000 ;
  SIZE 0.2100 BY 0.1440 ;
  SYMMETRY X Y ;
  SITE i3d_16A ;
  PIN VDD_2
    DIRECTION INOUT ;
    USE POWER ;
    PORT
      LAYER BPR ;
        RECT -0.0160 -0.0135 0.2260 0.0135 ;
    END
  END VDD_2
  PIN VDD_1
    DIRECTION INOUT ;
    USE POWER ;
    PORT
      LAYER BPR ;
        RECT -0.0160 0.1305 0.2260 0.1575 ;
    END
  END VDD_1
  PIN VSS
    DIRECTION INOUT ;
    USE GROUND ;
    PORT
      LAYER BPR ;
        RECT -0.0160 0.0585 0.2260 0.0855 ;
    END
  END VSS
  PIN Z
    DIRECTION OUTPUT ;
    USE SIGNAL ;
    PORT
      LAYER M1 ;
        RECT 0.0570 0.0030 0.0690 0.0870 ;
    END
  END Z
  PIN B
    DIRECTION INPUT ;
    USE SIGNAL ;
    PORT
      LAYER M1 ;
        RECT 0.1830 0.0390 0.1950 0.1050 ;
    END
  END B
  PIN A
    DIRECTION INPUT ;
    USE SIGNAL ;
    PORT
      LAYER M1 ;
        RECT 0.1410 0.0570 0.1530 0.1410 ;
    END
  END A
  OBS
    LAYER M1 ;
      RECT 0.0150 0.0210 0.0270 0.1410 ;
  END
END XOR2_X1

MACRO XOR2_X2
  CLASS CORE ;
  FOREIGN XOR2_X2 0 0 ;
  ORIGIN 0.0000 0.0000 ;
  SIZE 0.2100 BY 0.1440 ;
  SYMMETRY X Y ;
  SITE i3d_16A ;
  PIN VDD
    DIRECTION INOUT ;
    USE POWER ;
    PORT
      LAYER BPR ;
        RECT -0.0160 -0.0135 0.2260 0.0135 ;
        RECT -0.0160 0.1305 0.2260 0.1575 ;
    END
  END VDD
  PIN VSS
    DIRECTION INOUT ;
    USE GROUND ;
    PORT
      LAYER BPR ;
        RECT -0.0160 0.0585 0.2260 0.0855 ;
    END
  END VSS
  PIN Z
    DIRECTION OUTPUT ;
    USE SIGNAL ;
    PORT
      LAYER M1 ;
        RECT 0.0150 0.0030 0.0270 0.1235 ;
    END
  END Z
  PIN A
    DIRECTION INPUT ;
    USE SIGNAL ;
    PORT
      LAYER M1 ;
        RECT 0.0990 0.0210 0.1110 0.1230 ;
    END
  END A
  PIN B
    DIRECTION INPUT ;
    USE SIGNAL ;
    PORT
      LAYER M1 ;
        RECT 0.1410 0.0210 0.1530 0.1230 ;
    END
  END B
  OBS
    LAYER M1 ;
      RECT 0.0575 0.0580 0.0680 0.0865 ;
  END
END XOR2_X2

END LIBRARY
